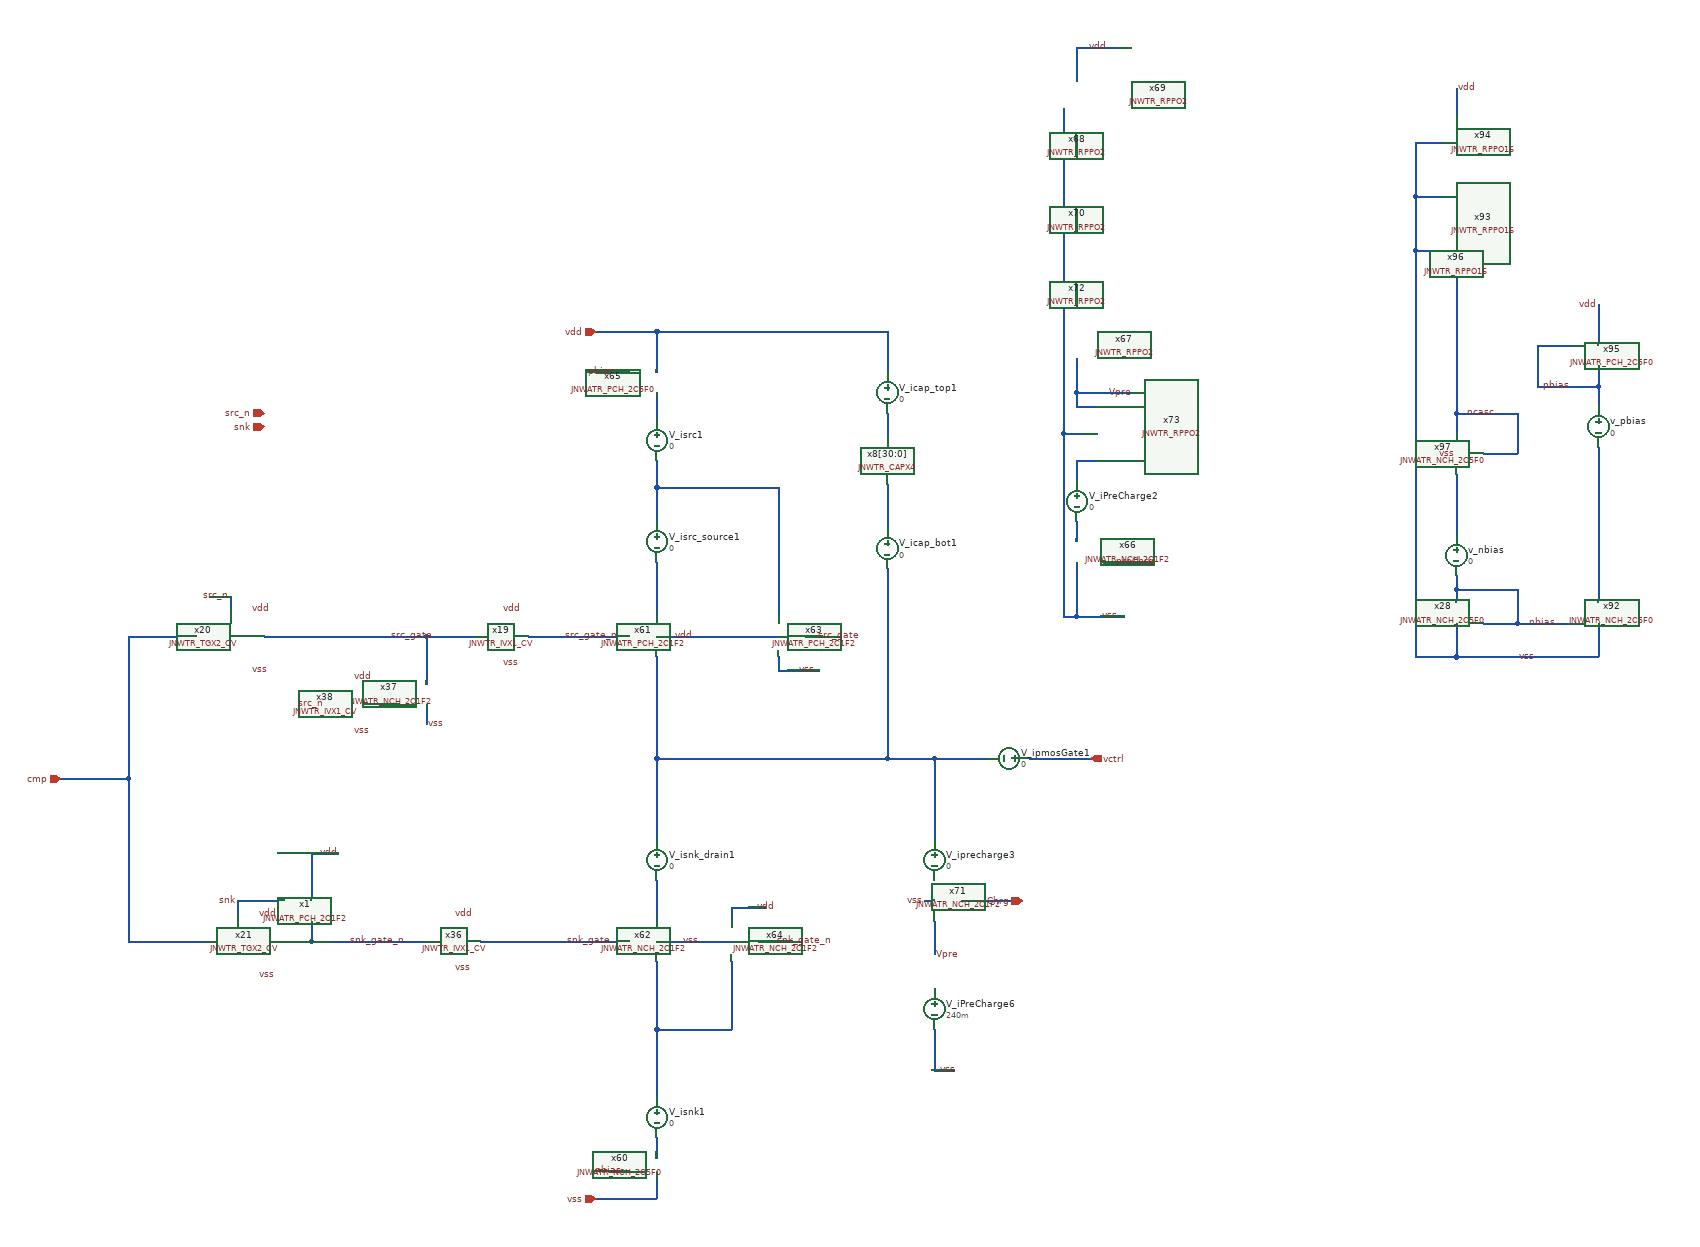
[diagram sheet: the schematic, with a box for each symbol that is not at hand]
v {xschem version=3.4.6 file_version=1.2}
G {}
K {}
V {}
S {}
E {}
N -180 -1190 -180 -1130 {
lab=vdd}
N -180 50 -180 90 {
lab=vss}
N -270 -1130 -220 -1130 {
lab=pbias}
N -250 50 -220 50 {
lab=nbias}
N 440 -1100 520 -1100 {
lab=Vpre}
N -180 -560 -180 -440 {
lab=#net1}
N 0 -710 0 -690 {
lab=vss}
N 0 -690 60 -690 {
lab=vss}
N 40 -740 65 -740 {
lab=src_gate}
N -70 -340 -70 -320 {
lab=vdd}
N -70 -340 -20 -340 {
lab=vdd}
N -30 -290 20 -290 {
lab=snk_gate_n}
N -180 0 -180 30 {
lab=#net2}
N -180 -1100 -180 -1060 {
lab=#net3}
N 440 -850 440 -770 {
lab=vss}
N 480 -850 550 -850 {
lab=preChrg}
N 440 -910 440 -880 {
lab=#net4}
N 440 -1000 440 -970 {
lab=#net5}
N 440 -770 510 -770 {
lab=vss}
N 420 -770 440 -770 {
lab=vss}
N 440 -1480 440 -1450 {
lab=#net6}
N 440 -1610 440 -1560 {
lab=vdd}
N 440 -1610 500 -1610 {
lab=vdd}
N 440 -1370 440 -1340 {
lab=#net7}
N -180 -960 0 -960 {
lab=#net8}
N -270 90 -180 90 {
lab=vss}
N -180 -740 0 -740 {
lab=vdd}
N -180 -290 -70 -290 {
lab=vss}
N -180 -160 -180 -60 {
lab=#net9}
N -70 -260 -70 -160 {
lab=#net9}
N -180 -160 -70 -160 {
lab=#net9}
N -180 -260 -180 -160 {
lab=#net9}
N 0 -960 0 -770 {
lab=#net8}
N 160 -965 160 -900 {
lab=#net10}
N 160 -840 160 -560 {
lab=#net1}
N 230 -560 310 -560 {
lab=#net1}
N 370 -560 460 -560 {
lab=vctrl}
N 160 -1070 160 -1035 {
lab=#net11}
N 160 -1190 160 -1130 {
lab=vdd}
N -180 -960 -180 -910 {
lab=#net8}
N -180 -850 -180 -770 {
lab=#net12}
N 270 -350 360 -350 {
lab=preChrg}
N 215 -350 230 -350 {
lab=vss}
N 230 -560 230 -440 {
lab=#net1}
N 440 -1100 440 -1080 {lab=Vpre}
N 420 -1040 420 -770 {
lab=vss}
N 440 -1080 470 -1080 {lab=Vpre}
N 440 -1000 470 -1000 {lab=#net5}
N 420 -1040 450 -1040 {lab=vss}
N 440 -1150 440 -1100 {lab=Vpre}
N 440 -1260 440 -1230 {lab=#net13}
N 420 -1520 420 -1040 {
lab=vss}
N 230 -160 230 -100 {lab=vss}
N 230 -100 260 -100 {lab=vss}
N 1000 -810 1090 -810 {
lab=nbias}
N 1000 -810 1000 -790 {
lab=nbias}
N 1210 -1140 1210 -1110 {
lab=pbias}
N 1120 -1110 1210 -1110 {
lab=pbias}
N 1120 -1170 1120 -1110 {
lab=pbias}
N 1120 -1170 1170 -1170 {
lab=pbias}
N 1210 -1230 1210 -1170 {
lab=vdd}
N 1000 -760 1000 -710 {
lab=vss}
N 940 -710 1000 -710 {
lab=vss}
N 1090 -810 1090 -760 {
lab=nbias}
N 1040 -760 1090 -760 {
lab=nbias}
N 1210 -760 1210 -710 {
lab=vss}
N 1090 -760 1170 -760 {
lab=nbias}
N 1210 -1110 1210 -1080 {
lab=pbias}
N 940 -1310 980 -1310 {
lab=vss}
N 1000 -1550 1000 -1510 {
lab=vdd}
N 940 -1390 940 -1310 {
lab=vss}
N 940 -1310 940 -710 {
lab=vss}
N 1000 -710 1210 -710 {
lab=vss}
N 940 -1390 980 -1390 {
lab=vss}
N 940 -1470 940 -1390 {
lab=vss}
N 1000 -830 1000 -810 {lab=nbias}
N 1210 -1020 1210 -790 {lab=#net14}
N 1000 -1270 1000 -1070 {lab=ncasc}
N 1000 -1070 1090 -1070 {lab=ncasc}
N 1090 -1070 1090 -1010 {lab=ncasc}
N 1000 -1070 1000 -1040 {lab=ncasc}
N 1040 -1010 1090 -1010 {lab=ncasc}
N 1000 -980 1000 -890 {lab=#net15}
N 940 -1470 980 -1470 {lab=vss}
N -1060 -530 -960 -530 {lab=cmp}
N -960 -530 -960 -290 {lab=cmp}
N -960 -740 -960 -530 {lab=cmp}
N -810 -800 -810 -780 {lab=src_n}
N -840 -800 -810 -800 {lab=src_n}
N -520 -740 -450 -740 {lab=src_gate}
N -800 -350 -800 -330 {lab=snk}
N -960 -740 -860 -740 {lab=cmp}
N -960 -290 -850 -290 {lab=cmp}
N -520 -640 -520 -610 {lab=vss}
N -590 -640 -560 -640 {lab=#net16}
N -440 -290 -220 -290 {lab=snk_gate}
N -690 -420 -690 -350 {lab=vdd}
N -690 -420 -650 -420 {lab=vdd}
N -800 -350 -730 -350 {lab=snk}
N -690 -320 -690 -290 {lab=snk_gate_n}
N -750 -290 -690 -290 {lab=snk_gate_n}
N -690 -290 -520 -290 {lab=snk_gate_n}
N -370 -740 -220 -740 {lab=src_gate_n}
N -520 -740 -520 -670 {lab=src_gate}
N -760 -740 -520 -740 {lab=src_gate}
N -180 -560 160 -560 {lab=#net1}
N -180 -710 -180 -560 {
lab=#net1}
N 160 -560 230 -560 {lab=#net1}
N -180 -380 -180 -320 {lab=#net17}
N -180 -1190 160 -1190 {lab=vdd}
N -270 -1190 -180 -1190 {lab=vdd}
N -180 -1000 -180 -960 {lab=#net8}
N 230 -320 230 -270 {lab=Vpre}
C {devices/ipin.sym} -270 -1190 0 0 {name=p113 lab=vdd}
C {devices/opin.sym} 460 -560 0 0 {name=p114 lab=vctrl}
C {devices/ipin.sym} -270 90 0 0 {name=p115 lab=vss
}
C {JNW_TR_SKY130A/JNWTR_CAPX4.sym} 160 -975 0 0 {name=x8[30:0]}
C {devices/ipin.sym} 360 -350 2 0 {name=p116 lab=preChrg
}
C {devices/lab_wire.sym} 455 -1610 0 1 {name=p117 sig_type=std_logic lab=vdd}
C {JNW_ATR_SKY130A/JNWATR_NCH_2C5F0.sym} -220 50 0 0 {name=x60 }
C {devices/lab_wire.sym} -155 -740 0 1 {name=p118 sig_type=std_logic lab=vdd}
C {devices/lab_wire.sym} 475 -770 0 1 {name=p119 sig_type=std_logic lab=vss}
C {devices/lab_wire.sym} 485 -1100 0 1 {name=p120 sig_type=std_logic lab=Vpre}
C {JNW_ATR_SKY130A/JNWATR_PCH_2C1F2.sym} -220 -740 0 0 {name=x61 }
C {JNW_ATR_SKY130A/JNWATR_NCH_2C1F2.sym} -220 -290 0 0 {name=x62 }
C {JNW_ATR_SKY130A/JNWATR_PCH_2C1F2.sym} 40 -740 0 1 {name=x63 }
C {devices/lab_wire.sym} 55 -690 0 0 {name=p121 sig_type=std_logic lab=vss}
C {JNW_ATR_SKY130A/JNWATR_NCH_2C1F2.sym} -30 -290 0 1 {name=x64 }
C {devices/lab_wire.sym} -115 -290 0 0 {name=p123 sig_type=std_logic lab=vss}
C {devices/lab_wire.sym} -5 -290 0 1 {name=p124 sig_type=std_logic lab=snk_gate_n}
C {devices/vsource.sym} -180 -1030 0 0 {name=V_isrc1 value=0 savecurrent=true}
C {devices/vsource.sym} -180 -30 0 0 {name=V_isnk1 value=0 savecurrent=true}
C {JNW_ATR_SKY130A/JNWATR_PCH_2C5F0.sym} -220 -1130 0 0 {name=x65 }
C {devices/vsource.sym} 440 -940 0 0 {name=V_iPreCharge2 value=0 savecurrent=true}
C {JNW_ATR_SKY130A/JNWATR_NCH_2C1F2.sym} 480 -850 0 1 {name=x66 }
C {devices/lab_wire.sym} 495 -850 0 1 {name=p125 sig_type=std_logic lab=preChrg}
C {JNW_TR_SKY130A/JNWTR_RPPO2.sym} 440 -1080 1 0 {name=x67 }
C {JNW_TR_SKY130A/JNWTR_RPPO2.sym} 440 -1450 1 0 {name=x68 }
C {JNW_TR_SKY130A/JNWTR_RPPO2.sym} 440 -1560 1 0 {name=x69 }
C {JNW_TR_SKY130A/JNWTR_RPPO2.sym} 440 -1340 1 0 {name=x70 }
C {devices/vsource.sym} -180 -410 0 0 {name=V_isnk_drain1 value=0 savecurrent=true}
C {devices/vsource.sym} -180 -880 0 0 {name=V_isrc_source1 value=0 savecurrent=true}
C {devices/lab_wire.sym} -35 -340 0 1 {name=p126 sig_type=std_logic lab=vdd}
C {devices/vsource.sym} 160 -870 0 0 {name=V_icap_bot1 value=0 savecurrent=true}
C {devices/vsource.sym} 230 -410 0 0 {name=V_iprecharge3 value=0 savecurrent=true}
C {devices/vsource.sym} 340 -560 1 0 {name=V_ipmosGate1 value=0 savecurrent=true}
C {devices/vsource.sym} 160 -1100 0 0 {name=V_icap_top1 value=0 savecurrent=true}
C {JNW_ATR_SKY130A/JNWATR_NCH_2C1F2.sym} 270 -350 0 1 {name=x71 }
C {devices/lab_wire.sym} 215 -350 0 0 {name=p127 sig_type=std_logic lab=vss}
C {JNW_TR_SKY130A/JNWTR_RPPO2.sym} 440 -1230 1 0 {name=x72 }
C {JNW_TR_SKY130A/JNWTR_RPPO2.sym} 470 -1080 1 0 {name=x73 }
C {devices/ipin.sym} -760 -1050 0 0 {name=p128 lab=snk
}
C {devices/ipin.sym} -760 -1070 0 0 {name=p129 lab=src_n}
C {devices/vsource.sym} 230 -190 0 0 {name=V_iPreCharge6 value=240m savecurrent=true}
C {devices/lab_wire.sym} 235 -100 0 1 {name=p155 sig_type=std_logic lab=vss}
C {devices/lab_wire.sym} 1170 -1110 0 0 {name=p174 sig_type=std_logic lab=pbias}
C {devices/lab_wire.sym} 1000 -1550 0 1 {name=p175 sig_type=std_logic lab=vdd}
C {devices/lab_wire.sym} 1090 -710 0 1 {name=p176 sig_type=std_logic lab=vss}
C {JNW_ATR_SKY130A/JNWATR_NCH_2C5F0.sym} 1040 -760 0 1 {name=x28}
C {devices/lab_wire.sym} 1210 -1230 0 0 {name=p177 sig_type=std_logic lab=vdd}
C {JNW_ATR_SKY130A/JNWATR_NCH_2C5F0.sym} 1170 -760 0 0 {name=x92 }
C {devices/lab_wire.sym} 1150 -760 0 0 {name=p178 sig_type=std_logic lab=nbias}
C {devices/vsource.sym} 1000 -860 0 0 {name=v_nbias value=0 savecurrent=true}
C {devices/vsource.sym} 1210 -1050 0 0 {name=v_pbias value=0 savecurrent=true}
C {JNW_TR_SKY130A/JNWTR_RPPO16.sym} 1000 -1350 1 1 {name=x93 }
C {JNW_TR_SKY130A/JNWTR_RPPO16.sym} 1000 -1430 1 1 {name=x94 }
C {JNW_ATR_SKY130A/JNWATR_PCH_2C5F0.sym} 1170 -1170 0 0 {name=x95 }
C {JNW_TR_SKY130A/JNWTR_RPPO16.sym} 1000 -1270 1 1 {name=x96 }
C {JNW_ATR_SKY130A/JNWATR_NCH_2C5F0.sym} 1040 -1010 0 1 {name=x97 }
C {devices/lab_wire.sym} 1000 -1010 0 0 {name=p179 sig_type=std_logic lab=vss}
C {devices/lab_wire.sym} -240 -1130 0 0 {name=p180 sig_type=std_logic lab=pbias}
C {devices/lab_wire.sym} -230 50 0 0 {name=p181 sig_type=std_logic lab=nbias}
C {devices/lab_wire.sym} 1060 -1070 0 0 {name=p182 sig_type=std_logic lab=ncasc}
C {devices/lab_wire.sym} 230 -270 0 1 {name=p1 sig_type=std_logic lab=Vpre

}
C {devices/lab_wire.sym} -235 -740 0 0 {name=p55 sig_type=std_logic lab=src_gate_n}
C {devices/lab_wire.sym} -245 -290 0 0 {name=p56 sig_type=std_logic lab=snk_gate}
C {devices/ipin.sym} -1060 -530 0 0 {name=p57 lab=cmp}
C {devices/lab_wire.sym} -575 -740 0 1 {name=p58 sig_type=std_logic lab=src_gate}
C {JNW_TR_SKY130A/JNWTR_IVX1_CV.sym} -450 -740 0 0 {name=x19 }
C {JNW_TR_SKY130A/JNWTR_TGX2_CV.sym} -870 -740 0 0 {name=x20 }
C {devices/lab_wire.sym} -780 -780 0 1 {name=p62 sig_type=std_logic lab=vdd

}
C {devices/lab_wire.sym} -780 -690 0 1 {name=p63 sig_type=std_logic lab=vss

}
C {devices/lab_wire.sym} -810 -800 0 0 {name=p64 sig_type=std_logic lab=src_n

}
C {JNW_TR_SKY130A/JNWTR_TGX2_CV.sym} -860 -290 0 0 {name=x21 }
C {devices/lab_wire.sym} -770 -330 0 1 {name=p66 sig_type=std_logic lab=vdd

}
C {devices/lab_wire.sym} -770 -240 0 1 {name=p67 sig_type=std_logic lab=vss

}
C {devices/lab_wire.sym} -800 -350 0 0 {name=p68 sig_type=std_logic lab=snk

}
C {JNW_TR_SKY130A/JNWTR_IVX1_CV.sym} -520 -290 0 0 {name=x36 }
C {devices/lab_wire.sym} -480 -250 0 1 {name=p69 sig_type=std_logic lab=vss

}
C {devices/lab_wire.sym} -480 -330 0 1 {name=p70 sig_type=std_logic lab=vdd

}
C {JNW_ATR_SKY130A/JNWATR_NCH_2C1F2.sym} -560 -640 0 0 {name=x37 }
C {devices/lab_wire.sym} -520 -610 0 1 {name=p71 sig_type=std_logic lab=vss

}
C {JNW_TR_SKY130A/JNWTR_IVX1_CV.sym} -670 -640 0 0 {name=x38 }
C {devices/lab_wire.sym} -630 -600 0 1 {name=p72 sig_type=std_logic lab=vss

}
C {devices/lab_wire.sym} -630 -680 0 1 {name=p73 sig_type=std_logic lab=vdd

}
C {devices/lab_wire.sym} -670 -640 0 0 {name=p173 sig_type=std_logic lab=src_n

}
C {devices/lab_wire.sym} -680 -420 0 1 {name=p4 sig_type=std_logic lab=vdd

}
C {JNW_ATR_SKY130A/JNWATR_PCH_2C1F2.sym} -730 -350 0 0 {name=x1 }
C {devices/lab_wire.sym} 55 -740 0 1 {name=p3 sig_type=std_logic lab=src_gate}
C {devices/lab_wire.sym} -635 -290 0 1 {name=p2 sig_type=std_logic lab=snk_gate_n}
C {devices/lab_wire.sym} -410 -780 0 1 {name=p5 sig_type=std_logic lab=vdd

}
C {devices/lab_wire.sym} -410 -700 0 1 {name=p6 sig_type=std_logic lab=vss

}
